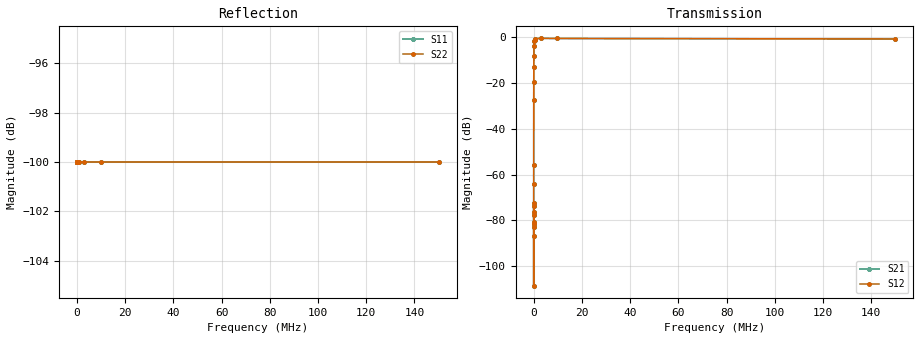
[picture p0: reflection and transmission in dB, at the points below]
! 5/13/2022 1:17 PM
! H:\MS4647B\Prototype_Data\HL9449-11\HL9449-11-typ-LFD.s2p
! CORRECTED DATA
# Hz S DB R 50.0
! FREQ  S11DB  S11A  S21DB  S21A  S12DB  S12A  S22DB  S22A
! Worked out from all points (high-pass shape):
!   401 points, 10 Hz to 150 MHz, reference 50 ohm
!   highest |S21| = -0.42 dB at 2.843 MHz (marker M1); lowest = -108.5 dB at 20.18 Hz (marker M2)
!   |S21| within 3 dB of the highest: 134.2 kHz to end of sweep
!   lowest |S11| = -100.0 dB at 10 Hz (marker M3), VSWR 1.00, Z = 50 + j0 ohm
!   |S11| at or under -10 dB: start of sweep to end of sweep
!   |S22| runs from -100.0 to -100.0 dB; largest |S21 - S12| = 0
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10  -100.00 0.0  -73.74 -73.7  -73.74 -73.7  -100.00 0.0
11.31933  -100.00 0.0  -81.72 -81.7  -81.72 -81.7  -100.00 0.0
11.79671  -100.00 0.0  -83.01 -83.0  -83.01 -83.0  -100.00 0.0
20.18291  -100.00 0.0  -108.53 -108.5  -108.53 -108.5  -100.00 0.0
159.2191  -100.00 0.0  -86.96 -87.0  -86.96 -87.0  -100.00 0.0
379.088  -100.00 0.0  -80.82 -80.8  -80.82 -80.8  -100.00 0.0
527.5479  -100.00 0.0  -77.65 -77.7  -77.65 -77.7  -100.00 0.0
597.1488  -100.00 0.0  -76.47 -76.5  -76.47 -76.5  -100.00 0.0
797.3779  -100.00 0.0  -72.41 -72.4  -72.41 -72.4  -100.00 0.0
1421.764  -100.00 0.0  -64.17 -64.2  -64.17 -64.2  -100.00 0.0
2535.074  -100.00 0.0  -55.61 -55.6  -55.61 -55.6  -100.00 0.0
14370.77  -100.00 0.0  -27.19 -27.2  -27.19 -27.2  -100.00 0.0
23591.9  -100.00 0.0  -19.65 -19.7  -19.65 -19.7  -100.00 0.0
40363.22  -100.00 0.0  -12.98 -13.0  -12.98 -13.0  -100.00 0.0
66262.62  -100.00 0.0  -8.02 -8.0  -8.02 -8.0  -100.00 0.0
128325.3  -100.00 0.0  -3.62 -3.6  -3.62 -3.6  -100.00 0.0
248516.9  -100.00 0.0  -1.46 -1.5  -1.46 -1.5  -100.00 0.0
360427.5  -100.00 0.0  -0.93 -0.9  -0.93 -0.9  -100.00 0.0
616653.1  -100.00 0.0  -0.59 -0.6  -0.59 -0.6  -100.00 0.0
2843344  -100.00 0.0  -0.42 -0.4  -0.42 -0.4  -100.00 0.0
9818298  -100.00 0.0  -0.47 -0.5  -0.47 -0.5  -100.00 0.0
1.5e8  -100.00 0.0  -0.68 -0.7  -0.68 -0.7  -100.00 0.0
